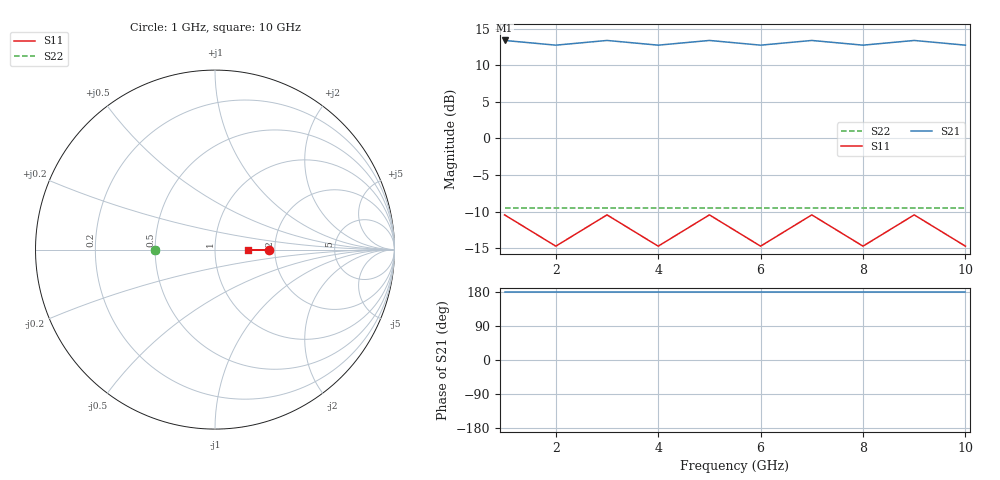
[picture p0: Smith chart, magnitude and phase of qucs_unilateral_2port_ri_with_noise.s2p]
# HZ S RI R 50
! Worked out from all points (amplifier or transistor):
!   10 points, 1 GHz to 10 GHz, reference 50 ohm
!   highest |S21| = 13.4 dB at 1 GHz (marker M1)
!   |S21| within 3 dB of that: start of sweep to end of sweep
!   lowest NFmin = 0.44 dB at 2 GHz
1e9  0.3 0  -4.667 4.68e-16  0 0  -0.3333 0
2e9  0.1833 0  -4.333 4.16e-16  0 0  -0.3333 0
3e9  0.3 0  -4.667 4.68e-16  0 0  -0.3333 0
4e9  0.1833 0  -4.333 4.16e-16  0 0  -0.3333 0
5e9  0.3 0  -4.667 4.68e-16  0 0  -0.3333 0
6e9  0.1833 0  -4.333 4.16e-16  0 0  -0.3333 0
7e9  0.3 0  -4.667 4.68e-16  0 0  -0.3333 0
8e9  0.1833 0  -4.333 4.16e-16  0 0  -0.3333 0
9e9  0.3 0  -4.667 4.68e-16  0 0  -0.3333 0
1e10  0.1833 0  -4.333 4.16e-16  0 0  -0.3333 0
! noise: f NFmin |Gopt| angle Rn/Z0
1e+09  0.9486  0.685  180  0.01826
2e+09  0.4448  0.6199  -180  0.0416
3e+09  0.9486  0.685  180  0.01826
4e+09  0.4448  0.6199  -180  0.0416
5e+09  0.9486  0.685  180  0.01826
6e+09  0.4448  0.6199  -180  0.0416
7e+09  0.9486  0.685  180  0.01826
8e+09  0.4448  0.6199  -180  0.0416
9e+09  0.9486  0.685  180  0.01826
1e+10  0.4448  0.6199  -180  0.0416
